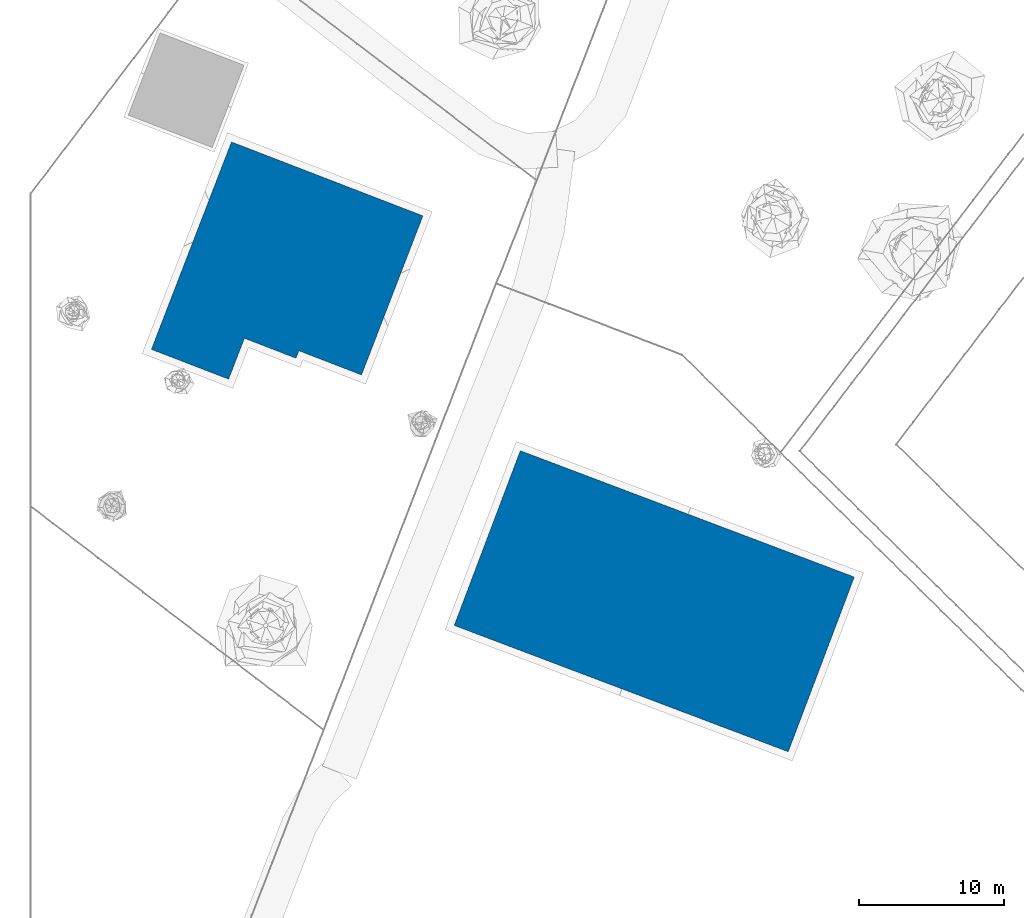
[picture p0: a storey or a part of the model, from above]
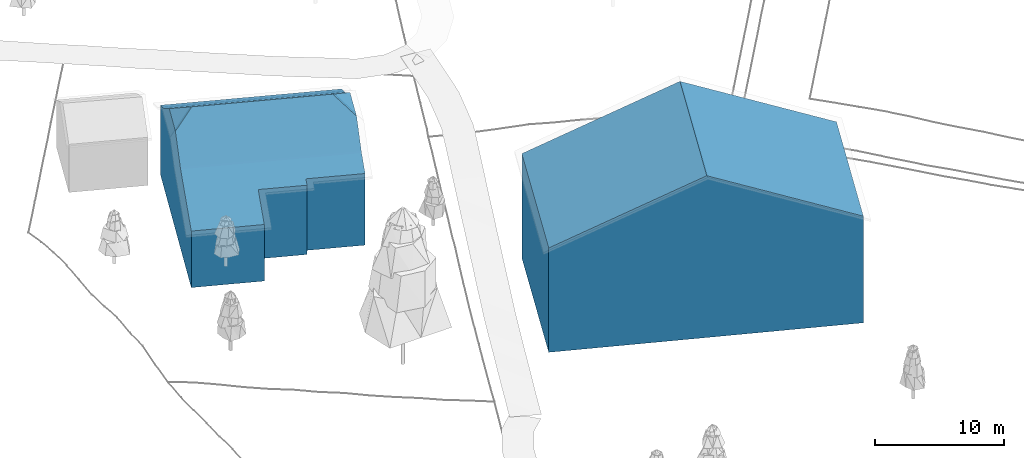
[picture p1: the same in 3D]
Properties of the parts of a building model (IFC4)

# File
Description: ViewDefinition [CoordinationView]
Time: 2026-02-18T16:27:45
Written by: IfcOpenShell 0.8.4-e8eb5e4
Made in: IfcOpenShell 0.8.4-e8eb5e4

# IfcSite (16)
Name | Description
CH907857693633
Buildings | 3D building models from swissBUILDINGS3D
Vegetation | Trees from swissTLM3D
Roads | Road network from swissTLM3D
Railways | Railway lines from swissTLM3D
Water | Water bodies from swissTLM3D
Parcels | Land parcels from cadastral register
Restrictions | RDPPF public law restrictions
Terrain | Terrain mesh from swissALTI3D
Bedrock | Bedrock geology from swissBEDROCK
Land_cover | Land cover polygons from swissTLM3D
Simulated_forest | Simulated trees within forest/wooded land cover polygons
Setbacks | Regulatory setback lines (Distance aux limites)
Water | Water land cover polygons
Wooded_Area | Wooded Area land cover polygons
Forest_Dense | Forest Dense land cover polygons

# IfcBuilding (9)
SwissBuildings3D_Properties - RoofType: unknown
Name | MinRoofElevation (m) | MaxRoofElevation (m) | FootprintArea (m2)
Building_5FC85BE9 | 619.16 | 623.12 | 133.324
Building_2D9329A2 | 612.86 | 618.71 | 198.571
Building_76F2A9BA | 616.07 | 618.38 | 59.9556
Building_7084BE5A | 610.24 | 615.64 | 129.21
Building_00CCDBD0 | 609.22 | 611.35 | 18.8518
Building_A8D2A459 | 613.27 | 615.91 | 71.2724
Building_6D479F88 | 620.98 | 623.62 | 173.352
Building_5E36CA29 | 611.85 | 624.43 | 222.846
Building_71E904FA | 613.95 | 620.34 | 83.4529

# IfcGeographicElement, Terrain
In: Terrain
PredefinedType: TERRAIN

# IfcGeographicElement: LAND_COVER (4)
PredefinedType: USERDEFINED
Name | In | CoverType | CoverName | Area_m2
LandCover_Water | Water | fliessgewaesser | Water | 252511
LandCover_Wooded_Area | Wooded_Area | gehoelzflaeche | Wooded Area | 3460.22
LandCover_Wooded_Area | Wooded_Area | gehoelzflaeche | Wooded Area | 2431.7
LandCover_Dense_Forest | Forest_Dense | wald | Dense Forest | 1546.1

# IfcGeographicElement: PARCEL (19)
In: Parcels
PredefinedType: USERDEFINED
Name | CodeNumber | EGRID | Area (m2)
Parcel_CH327864365790 | 557 | CH327864365790 | 3693
Parcel_CH133678576445 | 1007 | CH133678576445 | 9401
Parcel_CH333678576969 | DP 64 | CH333678576969 | 3230
Parcel_CH680583450962 | DP 116 | CH680583450962 | 2014
Parcel_CH698309054580 | DP 127 | CH698309054580 | 4895
Parcel_CH345736786432 | 139 | CH345736786432 | 11645
Parcel_CH156436785731 | 1008 | CH156436785731 | 2766
Parcel_CH333678576474 | 140 | CH333678576474 | 12543
Parcel_CH127864365761 | 1140 | CH127864365761 | 1283
Parcel_CH345736786927 | DP 65 | CH345736786927 | 3154
Parcel_CH907857693633 | 1014 | CH907857693633 | 7363
Parcel_CH256436785794 | 1012 | CH256436785794 | 1129
Parcel_CH267836576479 | 1013 | CH267836576479 | 1877
Parcel_CH375778643663 | 1009 | CH375778643663 | 2574
Parcel_CH945736786917 | 1017 | CH945736786917 | 34463
Parcel_CH307857643658 | 1176 | CH307857643658 | 2039
Parcel_CH207857643692 | 1116 | CH207857643692 | 1133
Parcel_CH933678576959 | 1016 | CH933678576959 | 195813
Parcel_CH293678645793 | 1120 | CH293678645793 | 1194

# IfcGeographicElement: ROAD (25)
In: Roads
PredefinedType: USERDEFINED
Pset_RoadCommon - RoadType: weg; Width: 2.5 m; IsTunnel: no
Name | IsBridge
24 x Road_weg | no
Road_weg | yes

# IfcGeographicElement: SETBACK (3)
In: Setbacks
PredefinedType: USERDEFINED
Pset_SetbackCommon - Source: user
Name | SetbackType | Distance_m
Limite de construction à 6.0m de la limite de propriété | construction | 6
Limite de modification du TN à 1.0m de la limite de propriété | nt_modification | 1
Distance à la route à 5.0m | road | 5

# IfcGeographicElement: VEGETATION (125)
PredefinedType: USERDEFINED
Name | In | Height (m) | CrownDiameter (m) | TreeType
Tree_einzelbaum | Vegetation | 6.18519 | 2.47408 | einzelbaum
Tree_einzelbaum | Vegetation | 10 | 4 | einzelbaum
Tree_einzelbaum | Vegetation | 4.1921 | 1.67684 | einzelbaum
Tree_einzelbaum | Vegetation | 13.2563 | 5.30252 | einzelbaum
Tree_einzelbaum | Vegetation | 22.024 | 8.8096 | einzelbaum
Tree_einzelbaum | Vegetation | 7.14372 | 2.85749 | einzelbaum
Tree_einzelbaum | Vegetation | 20.4306 | 8.17225 | einzelbaum
Tree_einzelbaum | Vegetation | 5.27469 | 2.10988 | einzelbaum
Tree_einzelbaum | Vegetation | 4.74552 | 1.89821 | einzelbaum
Tree_einzelbaum | Vegetation | 4.59065 | 1.83626 | einzelbaum
Tree_einzelbaum | Vegetation | 4.8278 | 1.93112 | einzelbaum
Tree_einzelbaum | Vegetation | 20.1764 | 8.07056 | einzelbaum
Tree_einzelbaum | Vegetation | 5.40547 | 2.16219 | einzelbaum
Tree_einzelbaum | Vegetation | 5.92687 | 2.37075 | einzelbaum
Tree_einzelbaum | Vegetation | 6.11433 | 2.44573 | einzelbaum
Tree_einzelbaum | Vegetation | 5.31819 | 2.12728 | einzelbaum
Tree_einzelbaum | Vegetation | 16.3784 | 6.55136 | einzelbaum
Tree_einzelbaum | Vegetation | 5.75556 | 2.30222 | einzelbaum
Tree_einzelbaum | Vegetation | 5.03463 | 2.01385 | einzelbaum
Tree_einzelbaum | Vegetation | 5.47504 | 2.19002 | einzelbaum
Tree_einzelbaum | Vegetation | 14.3365 | 5.7346 | einzelbaum
Tree_einzelbaum | Vegetation | 5.71607 | 2.28643 | einzelbaum
Tree_einzelbaum | Vegetation | 4.93299 | 1.9732 | einzelbaum
Tree_einzelbaum | Vegetation | 13.1578 | 5.26311 | einzelbaum
Tree_einzelbaum | Vegetation | 18.6405 | 7.45622 | einzelbaum
Tree_einzelbaum | Vegetation | 14.2753 | 5.7101 | einzelbaum
Tree_einzelbaum | Vegetation | 7.75781 | 3.10313 | einzelbaum
Tree_einzelbaum | Vegetation | 7.7948 | 3.11792 | einzelbaum
Tree_einzelbaum | Vegetation | 8.8403 | 3.53612 | einzelbaum
Tree_einzelbaum | Vegetation | 8.49782 | 3.39913 | einzelbaum
Tree_einzelbaum | Vegetation | 5.2038 | 2.08152 | einzelbaum
Tree_einzelbaum | Vegetation | 6.22445 | 2.48978 | einzelbaum
Tree_einzelbaum | Vegetation | 20.5683 | 8.22732 | einzelbaum
Tree_einzelbaum | Vegetation | 20.7687 | 8.30747 | einzelbaum
Tree_einzelbaum | Vegetation | 5.2046 | 2.08184 | einzelbaum
Tree_einzelbaum | Vegetation | 7.90846 | 3.16338 | einzelbaum
Tree_einzelbaum | Vegetation | 14.0353 | 5.6141 | einzelbaum
Tree_einzelbaum | Vegetation | 4.96707 | 1.98683 | einzelbaum
Tree_einzelbaum | Vegetation | 10.6658 | 4.26633 | einzelbaum
Tree_einzelbaum | Vegetation | 13.3946 | 5.35784 | einzelbaum
Tree_SIMULATED_WOODED_AREA | Simulated_forest | 11.0046 | 4.40184 | SIMULATED_WOODED_AREA
Tree_SIMULATED_WOODED_AREA | Simulated_forest | 8.87927 | 3.55171 | SIMULATED_WOODED_AREA
Tree_SIMULATED_WOODED_AREA | Simulated_forest | 12.6678 | 5.06714 | SIMULATED_WOODED_AREA
Tree_SIMULATED_WOODED_AREA | Simulated_forest | 9.59198 | 3.83679 | SIMULATED_WOODED_AREA
Tree_SIMULATED_WOODED_AREA | Simulated_forest | 8.17384 | 3.26954 | SIMULATED_WOODED_AREA
Tree_SIMULATED_WOODED_AREA | Simulated_forest | 9.26999 | 3.708 | SIMULATED_WOODED_AREA
Tree_SIMULATED_WOODED_AREA | Simulated_forest | 9.31764 | 3.72705 | SIMULATED_WOODED_AREA
Tree_SIMULATED_WOODED_AREA | Simulated_forest | 12.8121 | 5.12482 | SIMULATED_WOODED_AREA
Tree_SIMULATED_WOODED_AREA | Simulated_forest | 14.3866 | 5.75465 | SIMULATED_WOODED_AREA
Tree_SIMULATED_WOODED_AREA | Simulated_forest | 9.43 | 3.772 | SIMULATED_WOODED_AREA
Tree_SIMULATED_WOODED_AREA | Simulated_forest | 11.0391 | 4.41566 | SIMULATED_WOODED_AREA
Tree_SIMULATED_WOODED_AREA | Simulated_forest | 12.9642 | 5.18569 | SIMULATED_WOODED_AREA
Tree_SIMULATED_WOODED_AREA | Simulated_forest | 10.2186 | 4.08743 | SIMULATED_WOODED_AREA
Tree_SIMULATED_WOODED_AREA | Simulated_forest | 9.72099 | 3.88839 | SIMULATED_WOODED_AREA
Tree_SIMULATED_WOODED_AREA | Simulated_forest | 8.86282 | 3.54513 | SIMULATED_WOODED_AREA
Tree_SIMULATED_WOODED_AREA | Simulated_forest | 13.1695 | 5.26781 | SIMULATED_WOODED_AREA
Tree_SIMULATED_WOODED_AREA | Simulated_forest | 11.6519 | 4.66075 | SIMULATED_WOODED_AREA
Tree_SIMULATED_WOODED_AREA | Simulated_forest | 14.1987 | 5.67949 | SIMULATED_WOODED_AREA
Tree_SIMULATED_WOODED_AREA | Simulated_forest | 9.84292 | 3.93717 | SIMULATED_WOODED_AREA
Tree_SIMULATED_WOODED_AREA | Simulated_forest | 14.4043 | 5.76173 | SIMULATED_WOODED_AREA
Tree_SIMULATED_WOODED_AREA | Simulated_forest | 8.79582 | 3.51833 | SIMULATED_WOODED_AREA
Tree_SIMULATED_WOODED_AREA | Simulated_forest | 9.88425 | 3.9537 | SIMULATED_WOODED_AREA
Tree_SIMULATED_WOODED_AREA | Simulated_forest | 14.0354 | 5.61417 | SIMULATED_WOODED_AREA
Tree_SIMULATED_WOODED_AREA | Simulated_forest | 8.52403 | 3.40961 | SIMULATED_WOODED_AREA
Tree_SIMULATED_WOODED_AREA | Simulated_forest | 10.3093 | 4.12371 | SIMULATED_WOODED_AREA
Tree_SIMULATED_WOODED_AREA | Simulated_forest | 9.41347 | 3.76539 | SIMULATED_WOODED_AREA
Tree_SIMULATED_WOODED_AREA | Simulated_forest | 10.708 | 4.28319 | SIMULATED_WOODED_AREA
Tree_SIMULATED_WOODED_AREA | Simulated_forest | 8.42241 | 3.36896 | SIMULATED_WOODED_AREA
Tree_SIMULATED_WOODED_AREA | Simulated_forest | 14.768 | 5.90719 | SIMULATED_WOODED_AREA
Tree_SIMULATED_WOODED_AREA | Simulated_forest | 13.6873 | 5.47492 | SIMULATED_WOODED_AREA
Tree_SIMULATED_WOODED_AREA | Simulated_forest | 9.25549 | 3.70219 | SIMULATED_WOODED_AREA
Tree_SIMULATED_WOODED_AREA | Simulated_forest | 12.3207 | 4.9283 | SIMULATED_WOODED_AREA
Tree_SIMULATED_WOODED_AREA | Simulated_forest | 13.5215 | 5.4086 | SIMULATED_WOODED_AREA
Tree_SIMULATED_WOODED_AREA | Simulated_forest | 14.6022 | 5.84089 | SIMULATED_WOODED_AREA
Tree_SIMULATED_WOODED_AREA | Simulated_forest | 14.7047 | 5.88187 | SIMULATED_WOODED_AREA
Tree_SIMULATED_WOODED_AREA | Simulated_forest | 8.29094 | 3.31637 | SIMULATED_WOODED_AREA
Tree_SIMULATED_WOODED_AREA | Simulated_forest | 14.4762 | 5.79047 | SIMULATED_WOODED_AREA
Tree_SIMULATED_WOODED_AREA | Simulated_forest | 12.3137 | 4.9255 | SIMULATED_WOODED_AREA
Tree_SIMULATED_WOODED_AREA | Simulated_forest | 9.63282 | 3.85313 | SIMULATED_WOODED_AREA
Tree_SIMULATED_WOODED_AREA | Simulated_forest | 9.05002 | 3.62001 | SIMULATED_WOODED_AREA
Tree_SIMULATED_WOODED_AREA | Simulated_forest | 9.60781 | 3.84313 | SIMULATED_WOODED_AREA
Tree_SIMULATED_WOODED_AREA | Simulated_forest | 9.83298 | 3.93319 | SIMULATED_WOODED_AREA
Tree_SIMULATED_WOODED_AREA | Simulated_forest | 8.11428 | 3.24571 | SIMULATED_WOODED_AREA
Tree_SIMULATED_WOODED_AREA | Simulated_forest | 11.5429 | 4.61717 | SIMULATED_WOODED_AREA
Tree_SIMULATED_WOODED_AREA | Simulated_forest | 8.22128 | 3.28851 | SIMULATED_WOODED_AREA
Tree_SIMULATED_FOREST_DENSE | Simulated_forest | 16.5497 | 6.61986 | SIMULATED_FOREST_DENSE
Tree_SIMULATED_FOREST_DENSE | Simulated_forest | 20.7739 | 8.30955 | SIMULATED_FOREST_DENSE
Tree_SIMULATED_FOREST_DENSE | Simulated_forest | 24.6132 | 9.84528 | SIMULATED_FOREST_DENSE
Tree_SIMULATED_FOREST_DENSE | Simulated_forest | 21.5898 | 8.63592 | SIMULATED_FOREST_DENSE
Tree_SIMULATED_FOREST_DENSE | Simulated_forest | 20.4692 | 8.18769 | SIMULATED_FOREST_DENSE
Tree_SIMULATED_FOREST_DENSE | Simulated_forest | 21.6709 | 8.66838 | SIMULATED_FOREST_DENSE
Tree_SIMULATED_FOREST_DENSE | Simulated_forest | 16.8403 | 6.73611 | SIMULATED_FOREST_DENSE
Tree_SIMULATED_FOREST_DENSE | Simulated_forest | 21.0167 | 8.40666 | SIMULATED_FOREST_DENSE
Tree_SIMULATED_FOREST_DENSE | Simulated_forest | 20.9928 | 8.39712 | SIMULATED_FOREST_DENSE
Tree_SIMULATED_FOREST_DENSE | Simulated_forest | 17.7698 | 7.10793 | SIMULATED_FOREST_DENSE
Tree_SIMULATED_FOREST_DENSE | Simulated_forest | 16.3697 | 6.54789 | SIMULATED_FOREST_DENSE
Tree_SIMULATED_FOREST_DENSE | Simulated_forest | 17.9604 | 7.18417 | SIMULATED_FOREST_DENSE
Tree_SIMULATED_FOREST_DENSE | Simulated_forest | 15.0827 | 6.03307 | SIMULATED_FOREST_DENSE
Tree_SIMULATED_FOREST_DENSE | Simulated_forest | 15.0945 | 6.03779 | SIMULATED_FOREST_DENSE
Tree_SIMULATED_FOREST_DENSE | Simulated_forest | 21.7659 | 8.70636 | SIMULATED_FOREST_DENSE
Tree_SIMULATED_FOREST_DENSE | Simulated_forest | 19.7463 | 7.89851 | SIMULATED_FOREST_DENSE
Tree_SIMULATED_FOREST_DENSE | Simulated_forest | 17.6382 | 7.05527 | SIMULATED_FOREST_DENSE
Tree_SIMULATED_FOREST_DENSE | Simulated_forest | 16.2904 | 6.51616 | SIMULATED_FOREST_DENSE
Tree_SIMULATED_FOREST_DENSE | Simulated_forest | 23.0895 | 9.23578 | SIMULATED_FOREST_DENSE
Tree_SIMULATED_FOREST_DENSE | Simulated_forest | 23.9176 | 9.56704 | SIMULATED_FOREST_DENSE
Tree_SIMULATED_FOREST_DENSE | Simulated_forest | 21.2915 | 8.51659 | SIMULATED_FOREST_DENSE
Tree_SIMULATED_FOREST_DENSE | Simulated_forest | 19.264 | 7.70561 | SIMULATED_FOREST_DENSE
Tree_SIMULATED_FOREST_DENSE | Simulated_forest | 22.4036 | 8.96143 | SIMULATED_FOREST_DENSE
Tree_SIMULATED_FOREST_DENSE | Simulated_forest | 24.2909 | 9.71637 | SIMULATED_FOREST_DENSE
Tree_SIMULATED_FOREST_DENSE | Simulated_forest | 22.7583 | 9.10332 | SIMULATED_FOREST_DENSE
Tree_SIMULATED_FOREST_DENSE | Simulated_forest | 24.981 | 9.99239 | SIMULATED_FOREST_DENSE
Tree_SIMULATED_FOREST_DENSE | Simulated_forest | 15.0359 | 6.01437 | SIMULATED_FOREST_DENSE
Tree_SIMULATED_FOREST_DENSE | Simulated_forest | 15.5189 | 6.20755 | SIMULATED_FOREST_DENSE
Tree_SIMULATED_FOREST_DENSE | Simulated_forest | 23.6026 | 9.44104 | SIMULATED_FOREST_DENSE
Tree_SIMULATED_FOREST_DENSE | Simulated_forest | 18.9636 | 7.58544 | SIMULATED_FOREST_DENSE
Tree_SIMULATED_FOREST_DENSE | Simulated_forest | 16.3793 | 6.55171 | SIMULATED_FOREST_DENSE
Tree_SIMULATED_FOREST_DENSE | Simulated_forest | 17.7487 | 7.09947 | SIMULATED_FOREST_DENSE
Tree_SIMULATED_FOREST_DENSE | Simulated_forest | 20.749 | 8.29958 | SIMULATED_FOREST_DENSE
Tree_SIMULATED_FOREST_DENSE | Simulated_forest | 15.0083 | 6.00333 | SIMULATED_FOREST_DENSE
Tree_SIMULATED_FOREST_DENSE | Simulated_forest | 15.1291 | 6.05166 | SIMULATED_FOREST_DENSE
Tree_SIMULATED_FOREST_DENSE | Simulated_forest | 23.5908 | 9.4363 | SIMULATED_FOREST_DENSE
Tree_SIMULATED_FOREST_DENSE | Simulated_forest | 21.8993 | 8.75971 | SIMULATED_FOREST_DENSE
Tree_SIMULATED_FOREST_DENSE | Simulated_forest | 21.0512 | 8.42047 | SIMULATED_FOREST_DENSE
Tree_SIMULATED_FOREST_DENSE | Simulated_forest | 24.1803 | 9.67213 | SIMULATED_FOREST_DENSE
Tree_SIMULATED_FOREST_DENSE | Simulated_forest | 22.1677 | 8.8671 | SIMULATED_FOREST_DENSE

# IfcGeographicElement: WATER, Le Talent
In: Water
PredefinedType: USERDEFINED
